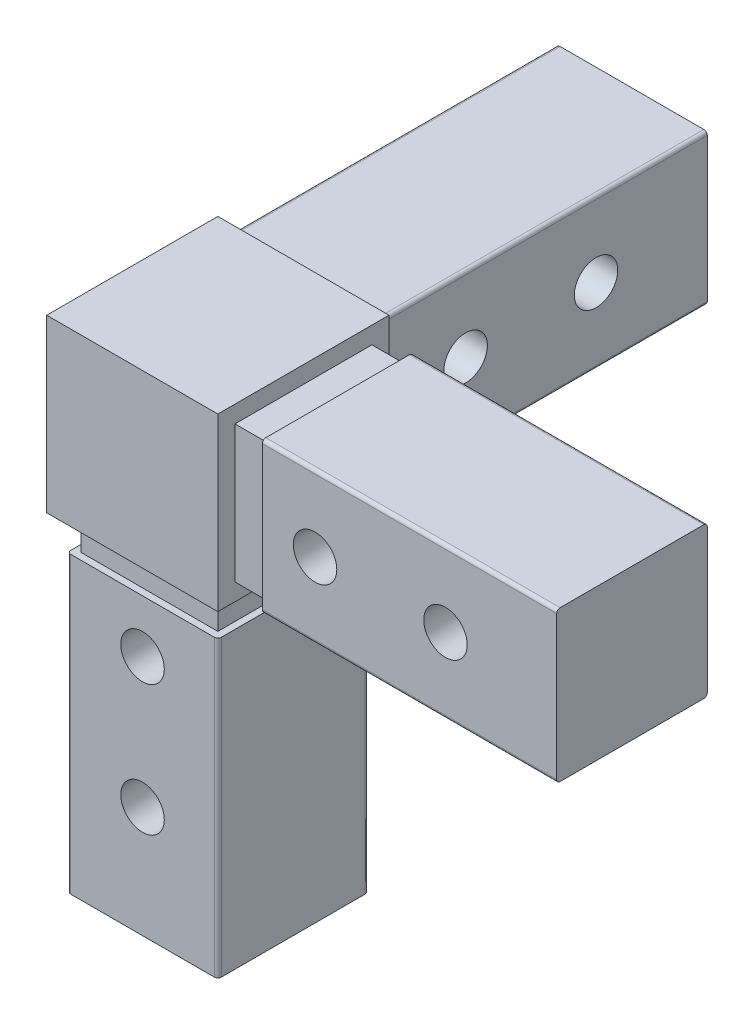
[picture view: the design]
ISO-10303-21;
HEADER;
FILE_DESCRIPTION(('STEP AP214'),'2;1');
FILE_NAME('part.step','',(''),(''),'','','');
FILE_SCHEMA(('AUTOMOTIVE_DESIGN { 1 0 10303 214 1 1 1 1 }'));
ENDSEC;
DATA;
#1=APPLICATION_CONTEXT('core data for automotive mechanical design processes');
#2=APPLICATION_PROTOCOL_DEFINITION('international standard','automotive_design',2000,#1);
#3=PRODUCT_CONTEXT('',#1,'mechanical');
#4=PRODUCT('Part','Part','',(#3));
#5=PRODUCT_RELATED_PRODUCT_CATEGORY('part','',(#4));
#6=PRODUCT_DEFINITION_FORMATION('','',#4);
#7=PRODUCT_DEFINITION_CONTEXT('part definition',#1,'design');
#8=PRODUCT_DEFINITION('design','',#6,#7);
#9=PRODUCT_DEFINITION_SHAPE('','',#8);
#10=(LENGTH_UNIT() NAMED_UNIT(*) SI_UNIT(.MILLI.,.METRE.));
#11=(NAMED_UNIT(*) PLANE_ANGLE_UNIT() SI_UNIT($,.RADIAN.));
#12=(NAMED_UNIT(*) SI_UNIT($,.STERADIAN.) SOLID_ANGLE_UNIT());
#13=UNCERTAINTY_MEASURE_WITH_UNIT(LENGTH_MEASURE(1.E-05),#10,'distance_accuracy_value','');
#14=(GEOMETRIC_REPRESENTATION_CONTEXT(3) GLOBAL_UNCERTAINTY_ASSIGNED_CONTEXT((#13)) GLOBAL_UNIT_ASSIGNED_CONTEXT((#10,
#11,#12)) REPRESENTATION_CONTEXT('',''));
#15=CARTESIAN_POINT('',(0.,0.,0.));
#16=DIRECTION('',(0.,0.,1.));
#17=DIRECTION('',(1.,0.,0.));
#18=AXIS2_PLACEMENT_3D('',#15,#16,#17);
#19=CARTESIAN_POINT('',(0.,0.,-12.5));
#20=DIRECTION('',(0.,0.,1.));
#21=DIRECTION('',(1.,0.,0.));
#22=AXIS2_PLACEMENT_3D('',#19,#20,#21);
#23=PLANE('',#22);
#24=DIRECTION('',(0.,1.,0.));
#25=VECTOR('',#24,1.);
#26=CARTESIAN_POINT('',(-12.5,12.5,-12.5));
#27=LINE('',#26,#25);
#28=CARTESIAN_POINT('',(-12.5,-12.5,-12.5));
#29=VERTEX_POINT('',#28);
#30=CARTESIAN_POINT('',(-12.5,12.5,-12.5));
#31=VERTEX_POINT('',#30);
#32=EDGE_CURVE('E502',#29,#31,#27,.T.);
#33=ORIENTED_EDGE('',*,*,#32,.T.);
#34=DIRECTION('',(1.,0.,0.));
#35=VECTOR('',#34,1.);
#36=CARTESIAN_POINT('',(12.5,12.5,-12.5));
#37=LINE('',#36,#35);
#38=CARTESIAN_POINT('',(12.5,12.5,-12.5));
#39=VERTEX_POINT('',#38);
#40=EDGE_CURVE('E505',#31,#39,#37,.T.);
#41=ORIENTED_EDGE('',*,*,#40,.T.);
#42=DIRECTION('',(0.,-1.,0.));
#43=VECTOR('',#42,1.);
#44=CARTESIAN_POINT('',(12.5,-12.5,-12.5));
#45=LINE('',#44,#43);
#46=CARTESIAN_POINT('',(12.5,-12.5,-12.5));
#47=VERTEX_POINT('',#46);
#48=EDGE_CURVE('E509',#39,#47,#45,.T.);
#49=ORIENTED_EDGE('',*,*,#48,.T.);
#50=DIRECTION('',(-1.,0.,0.));
#51=VECTOR('',#50,1.);
#52=CARTESIAN_POINT('',(-12.5,-12.5,-12.5));
#53=LINE('',#52,#51);
#54=EDGE_CURVE('E512',#47,#29,#53,.T.);
#55=ORIENTED_EDGE('',*,*,#54,.T.);
#56=EDGE_LOOP('',(#33,#41,#49,#55));
#57=FACE_BOUND('',#56,.T.);
#58=DIRECTION('',(0.,1.,0.));
#59=VECTOR('',#58,1.);
#60=CARTESIAN_POINT('',(-11.,11.,-12.5));
#61=LINE('',#60,#59);
#62=CARTESIAN_POINT('',(-11.,-10.4999999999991,-12.5));
#63=VERTEX_POINT('',#62);
#64=CARTESIAN_POINT('',(-11.,10.4999999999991,-12.5));
#65=VERTEX_POINT('',#64);
#66=EDGE_CURVE('E461',#63,#65,#61,.T.);
#67=ORIENTED_EDGE('',*,*,#66,.F.);
#68=CARTESIAN_POINT('',(-10.4999999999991,-10.4999999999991,-12.5));
#69=DIRECTION('',(0.,0.,1.));
#70=DIRECTION('',(1.,0.,0.));
#71=AXIS2_PLACEMENT_3D('',#68,#69,#70);
#72=CIRCLE('',#71,0.500000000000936);
#73=CARTESIAN_POINT('',(-10.4999999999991,-11.,-12.5));
#74=VERTEX_POINT('',#73);
#75=EDGE_CURVE('E11',#63,#74,#72,.T.);
#76=ORIENTED_EDGE('',*,*,#75,.T.);
#77=DIRECTION('',(-1.,0.,0.));
#78=VECTOR('',#77,1.);
#79=CARTESIAN_POINT('',(-11.,-11.,-12.5));
#80=LINE('',#79,#78);
#81=CARTESIAN_POINT('',(10.4999999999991,-11.,-12.5));
#82=VERTEX_POINT('',#81);
#83=EDGE_CURVE('E485',#82,#74,#80,.T.);
#84=ORIENTED_EDGE('',*,*,#83,.F.);
#85=CARTESIAN_POINT('',(10.4999999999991,-10.4999999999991,-12.5));
#86=DIRECTION('',(0.,0.,1.));
#87=DIRECTION('',(1.,0.,0.));
#88=AXIS2_PLACEMENT_3D('',#85,#86,#87);
#89=CIRCLE('',#88,0.500000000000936);
#90=CARTESIAN_POINT('',(11.,-10.4999999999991,-12.5));
#91=VERTEX_POINT('',#90);
#92=EDGE_CURVE('E445',#82,#91,#89,.T.);
#93=ORIENTED_EDGE('',*,*,#92,.T.);
#94=DIRECTION('',(0.,-1.,0.));
#95=VECTOR('',#94,1.);
#96=CARTESIAN_POINT('',(11.,-11.,-12.5));
#97=LINE('',#96,#95);
#98=CARTESIAN_POINT('',(11.,10.4999999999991,-12.5));
#99=VERTEX_POINT('',#98);
#100=EDGE_CURVE('E452',#99,#91,#97,.T.);
#101=ORIENTED_EDGE('',*,*,#100,.F.);
#102=CARTESIAN_POINT('',(10.4999999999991,10.4999999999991,-12.5));
#103=DIRECTION('',(0.,0.,1.));
#104=DIRECTION('',(1.,0.,0.));
#105=AXIS2_PLACEMENT_3D('',#102,#103,#104);
#106=CIRCLE('',#105,0.500000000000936);
#107=CARTESIAN_POINT('',(10.4999999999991,11.,-12.5));
#108=VERTEX_POINT('',#107);
#109=EDGE_CURVE('E447',#99,#108,#106,.T.);
#110=ORIENTED_EDGE('',*,*,#109,.T.);
#111=DIRECTION('',(1.,0.,0.));
#112=VECTOR('',#111,1.);
#113=CARTESIAN_POINT('',(11.,11.,-12.5));
#114=LINE('',#113,#112);
#115=CARTESIAN_POINT('',(-10.4999999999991,11.,-12.5));
#116=VERTEX_POINT('',#115);
#117=EDGE_CURVE('E450',#116,#108,#114,.T.);
#118=ORIENTED_EDGE('',*,*,#117,.F.);
#119=CARTESIAN_POINT('',(-10.4999999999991,10.4999999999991,-12.5));
#120=DIRECTION('',(0.,0.,1.));
#121=DIRECTION('',(1.,0.,0.));
#122=AXIS2_PLACEMENT_3D('',#119,#120,#121);
#123=CIRCLE('',#122,0.500000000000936);
#124=EDGE_CURVE('E54',#116,#65,#123,.T.);
#125=ORIENTED_EDGE('',*,*,#124,.T.);
#126=EDGE_LOOP('',(#67,#76,#84,#93,#101,#110,#118,#125));
#127=FACE_BOUND('',#126,.T.);
#128=ADVANCED_FACE('F46',(#57,#127),#23,.F.);
#129=CARTESIAN_POINT('',(0.,0.,10.));
#130=DIRECTION('',(0.,0.,1.));
#131=DIRECTION('',(1.,0.,0.));
#132=AXIS2_PLACEMENT_3D('',#129,#130,#131);
#133=PLANE('',#132);
#134=DIRECTION('',(-1.,0.,0.));
#135=VECTOR('',#134,1.);
#136=CARTESIAN_POINT('',(17.5,-10.,10.));
#137=LINE('',#136,#135);
#138=CARTESIAN_POINT('',(17.5,-10.,10.));
#139=VERTEX_POINT('',#138);
#140=CARTESIAN_POINT('',(12.5,-10.,10.));
#141=VERTEX_POINT('',#140);
#142=EDGE_CURVE('E283',#139,#141,#137,.T.);
#143=ORIENTED_EDGE('',*,*,#142,.F.);
#144=DIRECTION('',(0.,-1.,0.));
#145=VECTOR('',#144,1.);
#146=CARTESIAN_POINT('',(17.5,-11.,10.));
#147=LINE('',#146,#145);
#148=CARTESIAN_POINT('',(17.5,10.,10.));
#149=VERTEX_POINT('',#148);
#150=EDGE_CURVE('E278',#149,#139,#147,.T.);
#151=ORIENTED_EDGE('',*,*,#150,.F.);
#152=DIRECTION('',(-1.,0.,0.));
#153=VECTOR('',#152,1.);
#154=CARTESIAN_POINT('',(12.5,10.,10.));
#155=LINE('',#154,#153);
#156=CARTESIAN_POINT('',(12.5,10.,10.));
#157=VERTEX_POINT('',#156);
#158=EDGE_CURVE('E282',#149,#157,#155,.T.);
#159=ORIENTED_EDGE('',*,*,#158,.T.);
#160=DIRECTION('',(0.,1.,0.));
#161=VECTOR('',#160,1.);
#162=CARTESIAN_POINT('',(12.5,12.5,10.));
#163=LINE('',#162,#161);
#164=EDGE_CURVE('E532',#141,#157,#163,.T.);
#165=ORIENTED_EDGE('',*,*,#164,.F.);
#166=EDGE_LOOP('',(#143,#151,#159,#165));
#167=FACE_BOUND('',#166,.T.);
#168=ADVANCED_FACE('F280',(#167),#133,.T.);
#169=CARTESIAN_POINT('',(17.5,-10.,-10.));
#170=DIRECTION('',(0.,1.,0.));
#171=DIRECTION('',(0.,0.,1.));
#172=AXIS2_PLACEMENT_3D('',#169,#170,#171);
#173=PLANE('',#172);
#174=DIRECTION('',(0.,0.,-1.));
#175=VECTOR('',#174,1.);
#176=CARTESIAN_POINT('',(17.5,-10.,-11.));
#177=LINE('',#176,#175);
#178=CARTESIAN_POINT('',(17.5,-10.,-10.));
#179=VERTEX_POINT('',#178);
#180=EDGE_CURVE('E492',#139,#179,#177,.T.);
#181=ORIENTED_EDGE('',*,*,#180,.F.);
#182=ORIENTED_EDGE('',*,*,#142,.T.);
#183=DIRECTION('',(0.,0.,-1.));
#184=VECTOR('',#183,1.);
#185=CARTESIAN_POINT('',(12.5,-10.,-10.));
#186=LINE('',#185,#184);
#187=CARTESIAN_POINT('',(12.5,-10.,-10.));
#188=VERTEX_POINT('',#187);
#189=EDGE_CURVE('E311',#141,#188,#186,.T.);
#190=ORIENTED_EDGE('',*,*,#189,.T.);
#191=DIRECTION('',(-1.,0.,0.));
#192=VECTOR('',#191,1.);
#193=CARTESIAN_POINT('',(17.5,-10.,-10.));
#194=LINE('',#193,#192);
#195=EDGE_CURVE('E307',#179,#188,#194,.T.);
#196=ORIENTED_EDGE('',*,*,#195,.F.);
#197=EDGE_LOOP('',(#181,#182,#190,#196));
#198=FACE_BOUND('',#197,.T.);
#199=ADVANCED_FACE('F631',(#198),#173,.F.);
#200=CARTESIAN_POINT('',(0.,0.,-10.));
#201=DIRECTION('',(0.,0.,1.));
#202=DIRECTION('',(1.,0.,0.));
#203=AXIS2_PLACEMENT_3D('',#200,#201,#202);
#204=PLANE('',#203);
#205=DIRECTION('',(0.,-1.,0.));
#206=VECTOR('',#205,1.);
#207=CARTESIAN_POINT('',(12.5,-12.5,-10.));
#208=LINE('',#207,#206);
#209=CARTESIAN_POINT('',(12.5,10.,-10.));
#210=VERTEX_POINT('',#209);
#211=EDGE_CURVE('E500',#210,#188,#208,.T.);
#212=ORIENTED_EDGE('',*,*,#211,.F.);
#213=DIRECTION('',(-1.,0.,0.));
#214=VECTOR('',#213,1.);
#215=CARTESIAN_POINT('',(12.5,10.,-10.));
#216=LINE('',#215,#214);
#217=CARTESIAN_POINT('',(17.5,10.,-10.));
#218=VERTEX_POINT('',#217);
#219=EDGE_CURVE('E339',#218,#210,#216,.T.);
#220=ORIENTED_EDGE('',*,*,#219,.F.);
#221=DIRECTION('',(0.,1.,0.));
#222=VECTOR('',#221,1.);
#223=CARTESIAN_POINT('',(17.5,10.,-10.));
#224=LINE('',#223,#222);
#225=EDGE_CURVE('E306',#179,#218,#224,.T.);
#226=ORIENTED_EDGE('',*,*,#225,.F.);
#227=ORIENTED_EDGE('',*,*,#195,.T.);
#228=EDGE_LOOP('',(#212,#220,#226,#227));
#229=FACE_BOUND('',#228,.T.);
#230=ADVANCED_FACE('F746',(#229),#204,.F.);
#231=DIRECTION('',(-1.,0.,0.));
#232=VECTOR('',#231,1.);
#233=CARTESIAN_POINT('',(-12.5,-12.5,-10.));
#234=LINE('',#233,#232);
#235=CARTESIAN_POINT('',(10.,-12.5,-10.));
#236=VERTEX_POINT('',#235);
#237=CARTESIAN_POINT('',(-10.,-12.5,-10.));
#238=VERTEX_POINT('',#237);
#239=EDGE_CURVE('E506',#236,#238,#234,.T.);
#240=ORIENTED_EDGE('',*,*,#239,.F.);
#241=DIRECTION('',(0.,1.,0.));
#242=VECTOR('',#241,1.);
#243=CARTESIAN_POINT('',(10.,-17.5,-10.));
#244=LINE('',#243,#242);
#245=CARTESIAN_POINT('',(10.,-17.5,-10.));
#246=VERTEX_POINT('',#245);
#247=EDGE_CURVE('E301',#246,#236,#244,.T.);
#248=ORIENTED_EDGE('',*,*,#247,.F.);
#249=DIRECTION('',(1.,0.,0.));
#250=VECTOR('',#249,1.);
#251=CARTESIAN_POINT('',(10.,-17.5,-10.));
#252=LINE('',#251,#250);
#253=CARTESIAN_POINT('',(-10.,-17.5,-10.));
#254=VERTEX_POINT('',#253);
#255=EDGE_CURVE('E320',#254,#246,#252,.T.);
#256=ORIENTED_EDGE('',*,*,#255,.F.);
#257=DIRECTION('',(0.,-1.,0.));
#258=VECTOR('',#257,1.);
#259=CARTESIAN_POINT('',(-10.,10.,-10.));
#260=LINE('',#259,#258);
#261=EDGE_CURVE('E341',#238,#254,#260,.T.);
#262=ORIENTED_EDGE('',*,*,#261,.F.);
#263=EDGE_LOOP('',(#240,#248,#256,#262));
#264=FACE_BOUND('',#263,.T.);
#265=ADVANCED_FACE('F734',(#264),#204,.F.);
#266=CARTESIAN_POINT('',(-10.,10.,-10.));
#267=DIRECTION('',(-1.,0.,0.));
#268=DIRECTION('',(0.,0.,1.));
#269=AXIS2_PLACEMENT_3D('',#266,#267,#268);
#270=PLANE('',#269);
#271=DIRECTION('',(0.,-1.,0.));
#272=VECTOR('',#271,1.);
#273=CARTESIAN_POINT('',(-10.,10.,10.));
#274=LINE('',#273,#272);
#275=CARTESIAN_POINT('',(-10.,-12.5,10.));
#276=VERTEX_POINT('',#275);
#277=CARTESIAN_POINT('',(-10.,-17.5,10.));
#278=VERTEX_POINT('',#277);
#279=EDGE_CURVE('E300',#276,#278,#274,.T.);
#280=ORIENTED_EDGE('',*,*,#279,.F.);
#281=DIRECTION('',(0.,0.,1.));
#282=VECTOR('',#281,1.);
#283=CARTESIAN_POINT('',(-10.,-12.5,12.5));
#284=LINE('',#283,#282);
#285=EDGE_CURVE('E515',#238,#276,#284,.T.);
#286=ORIENTED_EDGE('',*,*,#285,.F.);
#287=ORIENTED_EDGE('',*,*,#261,.T.);
#288=DIRECTION('',(0.,0.,-1.));
#289=VECTOR('',#288,1.);
#290=CARTESIAN_POINT('',(-10.,-17.5,-10.));
#291=LINE('',#290,#289);
#292=EDGE_CURVE('E329',#278,#254,#291,.T.);
#293=ORIENTED_EDGE('',*,*,#292,.F.);
#294=EDGE_LOOP('',(#280,#286,#287,#293));
#295=FACE_BOUND('',#294,.T.);
#296=ADVANCED_FACE('F731',(#295),#270,.T.);
#297=DIRECTION('',(0.,1.,0.));
#298=VECTOR('',#297,1.);
#299=CARTESIAN_POINT('',(10.,-17.5,10.));
#300=LINE('',#299,#298);
#301=CARTESIAN_POINT('',(10.,-17.5,10.));
#302=VERTEX_POINT('',#301);
#303=CARTESIAN_POINT('',(10.,-12.5,10.));
#304=VERTEX_POINT('',#303);
#305=EDGE_CURVE('E332',#302,#304,#300,.T.);
#306=ORIENTED_EDGE('',*,*,#305,.T.);
#307=DIRECTION('',(1.,0.,0.));
#308=VECTOR('',#307,1.);
#309=CARTESIAN_POINT('',(12.5,-12.5,10.));
#310=LINE('',#309,#308);
#311=EDGE_CURVE('E526',#276,#304,#310,.T.);
#312=ORIENTED_EDGE('',*,*,#311,.F.);
#313=ORIENTED_EDGE('',*,*,#279,.T.);
#314=DIRECTION('',(-1.,0.,0.));
#315=VECTOR('',#314,1.);
#316=CARTESIAN_POINT('',(-10.,-17.5,10.));
#317=LINE('',#316,#315);
#318=EDGE_CURVE('E326',#302,#278,#317,.T.);
#319=ORIENTED_EDGE('',*,*,#318,.F.);
#320=EDGE_LOOP('',(#306,#312,#313,#319));
#321=FACE_BOUND('',#320,.T.);
#322=ADVANCED_FACE('F633',(#321),#133,.T.);
#323=CARTESIAN_POINT('',(12.5,10.,-10.));
#324=DIRECTION('',(0.,1.,0.));
#325=DIRECTION('',(-1.,0.,0.));
#326=AXIS2_PLACEMENT_3D('',#323,#324,#325);
#327=PLANE('',#326);
#328=ORIENTED_EDGE('',*,*,#219,.T.);
#329=DIRECTION('',(0.,0.,-1.));
#330=VECTOR('',#329,1.);
#331=CARTESIAN_POINT('',(12.5,10.,-10.));
#332=LINE('',#331,#330);
#333=EDGE_CURVE('E299',#157,#210,#332,.T.);
#334=ORIENTED_EDGE('',*,*,#333,.F.);
#335=ORIENTED_EDGE('',*,*,#158,.F.);
#336=DIRECTION('',(0.,0.,1.));
#337=VECTOR('',#336,1.);
#338=CARTESIAN_POINT('',(17.5,10.,10.));
#339=LINE('',#338,#337);
#340=EDGE_CURVE('E296',#218,#149,#339,.T.);
#341=ORIENTED_EDGE('',*,*,#340,.F.);
#342=EDGE_LOOP('',(#328,#334,#335,#341));
#343=FACE_BOUND('',#342,.T.);
#344=ADVANCED_FACE('F295',(#343),#327,.T.);
#345=CARTESIAN_POINT('',(12.5,-12.5,-10.));
#346=DIRECTION('',(1.,0.,0.));
#347=DIRECTION('',(0.,0.,-1.));
#348=AXIS2_PLACEMENT_3D('',#345,#346,#347);
#349=PLANE('',#348);
#350=ORIENTED_EDGE('',*,*,#333,.T.);
#351=ORIENTED_EDGE('',*,*,#211,.T.);
#352=ORIENTED_EDGE('',*,*,#189,.F.);
#353=ORIENTED_EDGE('',*,*,#164,.T.);
#354=EDGE_LOOP('',(#350,#351,#352,#353));
#355=FACE_BOUND('',#354,.T.);
#356=ORIENTED_EDGE('',*,*,#48,.F.);
#357=DIRECTION('',(0.,0.,-1.));
#358=VECTOR('',#357,1.);
#359=CARTESIAN_POINT('',(12.5,12.5,-10.));
#360=LINE('',#359,#358);
#361=CARTESIAN_POINT('',(12.5,12.5,12.5));
#362=VERTEX_POINT('',#361);
#363=EDGE_CURVE('E539',#362,#39,#360,.T.);
#364=ORIENTED_EDGE('',*,*,#363,.F.);
#365=DIRECTION('',(0.,1.,0.));
#366=VECTOR('',#365,1.);
#367=CARTESIAN_POINT('',(12.5,12.5,12.5));
#368=LINE('',#367,#366);
#369=CARTESIAN_POINT('',(12.5,-12.5,12.5));
#370=VERTEX_POINT('',#369);
#371=EDGE_CURVE('E531',#370,#362,#368,.T.);
#372=ORIENTED_EDGE('',*,*,#371,.F.);
#373=DIRECTION('',(0.,0.,1.));
#374=VECTOR('',#373,1.);
#375=CARTESIAN_POINT('',(12.5,-12.5,-10.));
#376=LINE('',#375,#374);
#377=EDGE_CURVE('E342',#47,#370,#376,.T.);
#378=ORIENTED_EDGE('',*,*,#377,.F.);
#379=EDGE_LOOP('',(#356,#364,#372,#378));
#380=FACE_BOUND('',#379,.T.);
#381=ADVANCED_FACE('F730',(#355,#380),#349,.T.);
#382=CARTESIAN_POINT('',(-10.,-12.5,-10.));
#383=DIRECTION('',(0.,-1.,0.));
#384=DIRECTION('',(0.,0.,-1.));
#385=AXIS2_PLACEMENT_3D('',#382,#383,#384);
#386=PLANE('',#385);
#387=ORIENTED_EDGE('',*,*,#54,.F.);
#388=ORIENTED_EDGE('',*,*,#377,.T.);
#389=DIRECTION('',(1.,0.,0.));
#390=VECTOR('',#389,1.);
#391=CARTESIAN_POINT('',(12.5,-12.5,12.5));
#392=LINE('',#391,#390);
#393=CARTESIAN_POINT('',(-12.5,-12.5,12.5));
#394=VERTEX_POINT('',#393);
#395=EDGE_CURVE('E528',#394,#370,#392,.T.);
#396=ORIENTED_EDGE('',*,*,#395,.F.);
#397=DIRECTION('',(0.,0.,1.));
#398=VECTOR('',#397,1.);
#399=CARTESIAN_POINT('',(-12.5,-12.5,12.5));
#400=LINE('',#399,#398);
#401=EDGE_CURVE('E518',#29,#394,#400,.T.);
#402=ORIENTED_EDGE('',*,*,#401,.F.);
#403=EDGE_LOOP('',(#387,#388,#396,#402));
#404=FACE_BOUND('',#403,.T.);
#405=DIRECTION('',(0.,0.,1.));
#406=VECTOR('',#405,1.);
#407=CARTESIAN_POINT('',(10.,-12.5,10.));
#408=LINE('',#407,#406);
#409=EDGE_CURVE('E319',#236,#304,#408,.T.);
#410=ORIENTED_EDGE('',*,*,#409,.F.);
#411=ORIENTED_EDGE('',*,*,#239,.T.);
#412=ORIENTED_EDGE('',*,*,#285,.T.);
#413=ORIENTED_EDGE('',*,*,#311,.T.);
#414=EDGE_LOOP('',(#410,#411,#412,#413));
#415=FACE_BOUND('',#414,.T.);
#416=ADVANCED_FACE('F736',(#404,#415),#386,.T.);
#417=CARTESIAN_POINT('',(10.,-17.5,10.));
#418=DIRECTION('',(-1.,0.,0.));
#419=DIRECTION('',(0.,0.,1.));
#420=AXIS2_PLACEMENT_3D('',#417,#418,#419);
#421=PLANE('',#420);
#422=ORIENTED_EDGE('',*,*,#409,.T.);
#423=ORIENTED_EDGE('',*,*,#305,.F.);
#424=DIRECTION('',(0.,0.,1.));
#425=VECTOR('',#424,1.);
#426=CARTESIAN_POINT('',(10.,-17.5,10.));
#427=LINE('',#426,#425);
#428=EDGE_CURVE('E323',#246,#302,#427,.T.);
#429=ORIENTED_EDGE('',*,*,#428,.F.);
#430=ORIENTED_EDGE('',*,*,#247,.T.);
#431=EDGE_LOOP('',(#422,#423,#429,#430));
#432=FACE_BOUND('',#431,.T.);
#433=ADVANCED_FACE('F739',(#432),#421,.F.);
#434=CARTESIAN_POINT('',(60.5,11.,-11.));
#435=DIRECTION('',(0.,0.,1.));
#436=DIRECTION('',(0.,-1.,0.));
#437=AXIS2_PLACEMENT_3D('',#434,#435,#436);
#438=PLANE('',#437);
#439=CARTESIAN_POINT('',(44.25,0.,-11.));
#440=DIRECTION('',(0.,0.,1.));
#441=DIRECTION('',(0.,-1.,0.));
#442=AXIS2_PLACEMENT_3D('',#439,#440,#441);
#443=CIRCLE('',#442,3.175);
#444=CARTESIAN_POINT('',(44.25,-3.175,-11.));
#445=VERTEX_POINT('',#444);
#446=EDGE_CURVE('E482',#445,#445,#443,.F.);
#447=ORIENTED_EDGE('',*,*,#446,.F.);
#448=EDGE_LOOP('',(#447));
#449=FACE_BOUND('',#448,.T.);
#450=CARTESIAN_POINT('',(25.2,0.,-11.));
#451=DIRECTION('',(0.,0.,1.));
#452=DIRECTION('',(0.,-1.,0.));
#453=AXIS2_PLACEMENT_3D('',#450,#451,#452);
#454=CIRCLE('',#453,3.175);
#455=CARTESIAN_POINT('',(25.2,-3.175,-11.));
#456=VERTEX_POINT('',#455);
#457=EDGE_CURVE('E1460',#456,#456,#454,.F.);
#458=ORIENTED_EDGE('',*,*,#457,.F.);
#459=EDGE_LOOP('',(#458));
#460=FACE_BOUND('',#459,.T.);
#461=DIRECTION('',(0.,1.,0.));
#462=VECTOR('',#461,1.);
#463=CARTESIAN_POINT('',(17.5,11.,-11.));
#464=LINE('',#463,#462);
#465=CARTESIAN_POINT('',(17.5,-10.4999999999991,-11.));
#466=VERTEX_POINT('',#465);
#467=CARTESIAN_POINT('',(17.5,10.4999999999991,-11.));
#468=VERTEX_POINT('',#467);
#469=EDGE_CURVE('E556',#466,#468,#464,.T.);
#470=ORIENTED_EDGE('',*,*,#469,.T.);
#471=DIRECTION('',(-1.,0.,0.));
#472=VECTOR('',#471,1.);
#473=CARTESIAN_POINT('',(60.5,10.4999999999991,-11.));
#474=LINE('',#473,#472);
#475=CARTESIAN_POINT('',(60.5,10.4999999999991,-11.));
#476=VERTEX_POINT('',#475);
#477=EDGE_CURVE('E406',#468,#476,#474,.F.);
#478=ORIENTED_EDGE('',*,*,#477,.T.);
#479=DIRECTION('',(0.,1.,0.));
#480=VECTOR('',#479,1.);
#481=CARTESIAN_POINT('',(60.5,11.,-11.));
#482=LINE('',#481,#480);
#483=CARTESIAN_POINT('',(60.5,-10.4999999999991,-11.));
#484=VERTEX_POINT('',#483);
#485=EDGE_CURVE('E567',#484,#476,#482,.T.);
#486=ORIENTED_EDGE('',*,*,#485,.F.);
#487=DIRECTION('',(1.,0.,0.));
#488=VECTOR('',#487,1.);
#489=CARTESIAN_POINT('',(60.5,-10.4999999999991,-11.));
#490=LINE('',#489,#488);
#491=EDGE_CURVE('E404',#484,#466,#490,.F.);
#492=ORIENTED_EDGE('',*,*,#491,.T.);
#493=EDGE_LOOP('',(#470,#478,#486,#492));
#494=FACE_BOUND('',#493,.T.);
#495=ADVANCED_FACE('F608',(#449,#460,#494),#438,.F.);
#496=CARTESIAN_POINT('',(60.5,11.,10.));
#497=DIRECTION('',(0.,-1.,0.));
#498=DIRECTION('',(0.,0.,-1.));
#499=AXIS2_PLACEMENT_3D('',#496,#497,#498);
#500=PLANE('',#499);
#501=DIRECTION('',(0.,0.,1.));
#502=VECTOR('',#501,1.);
#503=CARTESIAN_POINT('',(60.5,11.,10.));
#504=LINE('',#503,#502);
#505=CARTESIAN_POINT('',(60.5,11.,-10.4999999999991));
#506=VERTEX_POINT('',#505);
#507=CARTESIAN_POINT('',(60.5,11.,10.4999999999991));
#508=VERTEX_POINT('',#507);
#509=EDGE_CURVE('E316',#506,#508,#504,.T.);
#510=ORIENTED_EDGE('',*,*,#509,.F.);
#511=DIRECTION('',(-1.,0.,0.));
#512=VECTOR('',#511,1.);
#513=CARTESIAN_POINT('',(60.5,11.,-10.4999999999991));
#514=LINE('',#513,#512);
#515=CARTESIAN_POINT('',(17.5,11.,-10.4999999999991));
#516=VERTEX_POINT('',#515);
#517=EDGE_CURVE('E401',#506,#516,#514,.T.);
#518=ORIENTED_EDGE('',*,*,#517,.T.);
#519=DIRECTION('',(0.,0.,1.));
#520=VECTOR('',#519,1.);
#521=CARTESIAN_POINT('',(17.5,11.,10.));
#522=LINE('',#521,#520);
#523=CARTESIAN_POINT('',(17.5,11.,10.4999999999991));
#524=VERTEX_POINT('',#523);
#525=EDGE_CURVE('E570',#516,#524,#522,.T.);
#526=ORIENTED_EDGE('',*,*,#525,.T.);
#527=DIRECTION('',(-1.,0.,0.));
#528=VECTOR('',#527,1.);
#529=CARTESIAN_POINT('',(60.5,11.,10.4999999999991));
#530=LINE('',#529,#528);
#531=EDGE_CURVE('E399',#524,#508,#530,.F.);
#532=ORIENTED_EDGE('',*,*,#531,.T.);
#533=EDGE_LOOP('',(#510,#518,#526,#532));
#534=FACE_BOUND('',#533,.T.);
#535=ADVANCED_FACE('F579',(#534),#500,.F.);
#536=CARTESIAN_POINT('',(60.5,0.,0.));
#537=DIRECTION('',(-1.,0.,0.));
#538=DIRECTION('',(0.,0.,1.));
#539=AXIS2_PLACEMENT_3D('',#536,#537,#538);
#540=PLANE('',#539);
#541=DIRECTION('',(0.,1.,0.));
#542=VECTOR('',#541,1.);
#543=CARTESIAN_POINT('',(60.5,11.,11.));
#544=LINE('',#543,#542);
#545=CARTESIAN_POINT('',(60.5,-10.4999999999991,11.));
#546=VERTEX_POINT('',#545);
#547=CARTESIAN_POINT('',(60.5,10.4999999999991,11.));
#548=VERTEX_POINT('',#547);
#549=EDGE_CURVE('E490',#546,#548,#544,.T.);
#550=ORIENTED_EDGE('',*,*,#549,.F.);
#551=CARTESIAN_POINT('',(60.5,-10.4999999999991,10.4999999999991));
#552=DIRECTION('',(-1.,0.,0.));
#553=DIRECTION('',(0.,0.,1.));
#554=AXIS2_PLACEMENT_3D('',#551,#552,#553);
#555=CIRCLE('',#554,0.500000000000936);
#556=CARTESIAN_POINT('',(60.5,-11.,10.4999999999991));
#557=VERTEX_POINT('',#556);
#558=EDGE_CURVE('E384',#546,#557,#555,.F.);
#559=ORIENTED_EDGE('',*,*,#558,.T.);
#560=DIRECTION('',(0.,0.,1.));
#561=VECTOR('',#560,1.);
#562=CARTESIAN_POINT('',(60.5,-11.,10.));
#563=LINE('',#562,#561);
#564=CARTESIAN_POINT('',(60.5,-11.,-10.4999999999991));
#565=VERTEX_POINT('',#564);
#566=EDGE_CURVE('E497',#565,#557,#563,.T.);
#567=ORIENTED_EDGE('',*,*,#566,.F.);
#568=CARTESIAN_POINT('',(60.5,-10.4999999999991,-10.4999999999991));
#569=DIRECTION('',(-1.,0.,0.));
#570=DIRECTION('',(0.,0.,1.));
#571=AXIS2_PLACEMENT_3D('',#568,#569,#570);
#572=CIRCLE('',#571,0.500000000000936);
#573=EDGE_CURVE('E378',#565,#484,#572,.F.);
#574=ORIENTED_EDGE('',*,*,#573,.T.);
#575=ORIENTED_EDGE('',*,*,#485,.T.);
#576=CARTESIAN_POINT('',(60.5,10.4999999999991,-10.4999999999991));
#577=DIRECTION('',(-1.,0.,0.));
#578=DIRECTION('',(0.,0.,1.));
#579=AXIS2_PLACEMENT_3D('',#576,#577,#578);
#580=CIRCLE('',#579,0.500000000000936);
#581=EDGE_CURVE('E382',#476,#506,#580,.F.);
#582=ORIENTED_EDGE('',*,*,#581,.T.);
#583=ORIENTED_EDGE('',*,*,#509,.T.);
#584=CARTESIAN_POINT('',(60.5,10.4999999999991,10.4999999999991));
#585=DIRECTION('',(-1.,0.,0.));
#586=DIRECTION('',(0.,0.,1.));
#587=AXIS2_PLACEMENT_3D('',#584,#585,#586);
#588=CIRCLE('',#587,0.500000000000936);
#589=EDGE_CURVE('E380',#508,#548,#588,.F.);
#590=ORIENTED_EDGE('',*,*,#589,.T.);
#591=EDGE_LOOP('',(#550,#559,#567,#574,#575,#582,#583,#590));
#592=FACE_BOUND('',#591,.T.);
#593=ADVANCED_FACE('F587',(#592),#540,.F.);
#594=CARTESIAN_POINT('',(17.5,0.,0.));
#595=DIRECTION('',(-1.,0.,0.));
#596=DIRECTION('',(0.,0.,1.));
#597=AXIS2_PLACEMENT_3D('',#594,#595,#596);
#598=PLANE('',#597);
#599=ORIENTED_EDGE('',*,*,#340,.T.);
#600=ORIENTED_EDGE('',*,*,#150,.T.);
#601=ORIENTED_EDGE('',*,*,#180,.T.);
#602=ORIENTED_EDGE('',*,*,#225,.T.);
#603=EDGE_LOOP('',(#599,#600,#601,#602));
#604=FACE_BOUND('',#603,.T.);
#605=DIRECTION('',(0.,0.,-1.));
#606=VECTOR('',#605,1.);
#607=CARTESIAN_POINT('',(17.5,-11.,-11.));
#608=LINE('',#607,#606);
#609=CARTESIAN_POINT('',(17.5,-11.,10.4999999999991));
#610=VERTEX_POINT('',#609);
#611=CARTESIAN_POINT('',(17.5,-11.,-10.4999999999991));
#612=VERTEX_POINT('',#611);
#613=EDGE_CURVE('E494',#610,#612,#608,.T.);
#614=ORIENTED_EDGE('',*,*,#613,.F.);
#615=CARTESIAN_POINT('',(17.5,-10.4999999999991,10.4999999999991));
#616=DIRECTION('',(-1.,0.,0.));
#617=DIRECTION('',(0.,0.,1.));
#618=AXIS2_PLACEMENT_3D('',#615,#616,#617);
#619=CIRCLE('',#618,0.500000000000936);
#620=CARTESIAN_POINT('',(17.5,-10.4999999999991,11.));
#621=VERTEX_POINT('',#620);
#622=EDGE_CURVE('E397',#610,#621,#619,.T.);
#623=ORIENTED_EDGE('',*,*,#622,.T.);
#624=DIRECTION('',(0.,-1.,0.));
#625=VECTOR('',#624,1.);
#626=CARTESIAN_POINT('',(17.5,-11.,11.));
#627=LINE('',#626,#625);
#628=CARTESIAN_POINT('',(17.5,10.4999999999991,11.));
#629=VERTEX_POINT('',#628);
#630=EDGE_CURVE('E288',#629,#621,#627,.T.);
#631=ORIENTED_EDGE('',*,*,#630,.F.);
#632=CARTESIAN_POINT('',(17.5,10.4999999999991,10.4999999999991));
#633=DIRECTION('',(-1.,0.,0.));
#634=DIRECTION('',(0.,0.,1.));
#635=AXIS2_PLACEMENT_3D('',#632,#633,#634);
#636=CIRCLE('',#635,0.500000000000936);
#637=EDGE_CURVE('E393',#629,#524,#636,.T.);
#638=ORIENTED_EDGE('',*,*,#637,.T.);
#639=ORIENTED_EDGE('',*,*,#525,.F.);
#640=CARTESIAN_POINT('',(17.5,10.4999999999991,-10.4999999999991));
#641=DIRECTION('',(-1.,0.,0.));
#642=DIRECTION('',(0.,0.,1.));
#643=AXIS2_PLACEMENT_3D('',#640,#641,#642);
#644=CIRCLE('',#643,0.500000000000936);
#645=EDGE_CURVE('E395',#516,#468,#644,.T.);
#646=ORIENTED_EDGE('',*,*,#645,.T.);
#647=ORIENTED_EDGE('',*,*,#469,.F.);
#648=CARTESIAN_POINT('',(17.5,-10.4999999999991,-10.4999999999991));
#649=DIRECTION('',(-1.,0.,0.));
#650=DIRECTION('',(0.,0.,1.));
#651=AXIS2_PLACEMENT_3D('',#648,#649,#650);
#652=CIRCLE('',#651,0.500000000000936);
#653=EDGE_CURVE('E391',#466,#612,#652,.T.);
#654=ORIENTED_EDGE('',*,*,#653,.T.);
#655=EDGE_LOOP('',(#614,#623,#631,#638,#639,#646,#647,#654));
#656=FACE_BOUND('',#655,.T.);
#657=ADVANCED_FACE('F303',(#604,#656),#598,.T.);
#658=CARTESIAN_POINT('',(11.,-60.5,-11.));
#659=DIRECTION('',(0.,0.,-1.));
#660=DIRECTION('',(-1.,0.,0.));
#661=AXIS2_PLACEMENT_3D('',#658,#659,#660);
#662=PLANE('',#661);
#663=CARTESIAN_POINT('',(0.,-44.25,-11.));
#664=DIRECTION('',(0.,0.,-1.));
#665=DIRECTION('',(-1.,0.,0.));
#666=AXIS2_PLACEMENT_3D('',#663,#664,#665);
#667=CIRCLE('',#666,3.175);
#668=CARTESIAN_POINT('',(-3.175,-44.25,-11.));
#669=VERTEX_POINT('',#668);
#670=EDGE_CURVE('E1456',#669,#669,#667,.F.);
#671=ORIENTED_EDGE('',*,*,#670,.T.);
#672=EDGE_LOOP('',(#671));
#673=FACE_BOUND('',#672,.T.);
#674=CARTESIAN_POINT('',(0.,-25.2,-11.));
#675=DIRECTION('',(0.,0.,-1.));
#676=DIRECTION('',(-1.,0.,0.));
#677=AXIS2_PLACEMENT_3D('',#674,#675,#676);
#678=CIRCLE('',#677,3.175);
#679=CARTESIAN_POINT('',(-3.175,-25.2,-11.));
#680=VERTEX_POINT('',#679);
#681=EDGE_CURVE('E1445',#680,#680,#678,.F.);
#682=ORIENTED_EDGE('',*,*,#681,.T.);
#683=EDGE_LOOP('',(#682));
#684=FACE_BOUND('',#683,.T.);
#685=DIRECTION('',(-1.,0.,0.));
#686=VECTOR('',#685,1.);
#687=CARTESIAN_POINT('',(11.,-60.5,-11.));
#688=LINE('',#687,#686);
#689=CARTESIAN_POINT('',(10.4999999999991,-60.5,-11.));
#690=VERTEX_POINT('',#689);
#691=CARTESIAN_POINT('',(-10.4999999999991,-60.5,-11.));
#692=VERTEX_POINT('',#691);
#693=EDGE_CURVE('E543',#690,#692,#688,.T.);
#694=ORIENTED_EDGE('',*,*,#693,.T.);
#695=DIRECTION('',(0.,1.,0.));
#696=VECTOR('',#695,1.);
#697=CARTESIAN_POINT('',(-10.4999999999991,-60.5,-11.));
#698=LINE('',#697,#696);
#699=CARTESIAN_POINT('',(-10.4999999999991,-17.5,-11.));
#700=VERTEX_POINT('',#699);
#701=EDGE_CURVE('E442',#692,#700,#698,.T.);
#702=ORIENTED_EDGE('',*,*,#701,.T.);
#703=DIRECTION('',(-1.,0.,0.));
#704=VECTOR('',#703,1.);
#705=CARTESIAN_POINT('',(11.,-17.5,-11.));
#706=LINE('',#705,#704);
#707=CARTESIAN_POINT('',(10.4999999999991,-17.5,-11.));
#708=VERTEX_POINT('',#707);
#709=EDGE_CURVE('E541',#708,#700,#706,.T.);
#710=ORIENTED_EDGE('',*,*,#709,.F.);
#711=DIRECTION('',(0.,1.,0.));
#712=VECTOR('',#711,1.);
#713=CARTESIAN_POINT('',(10.4999999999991,-60.5,-11.));
#714=LINE('',#713,#712);
#715=EDGE_CURVE('E440',#708,#690,#714,.F.);
#716=ORIENTED_EDGE('',*,*,#715,.T.);
#717=EDGE_LOOP('',(#694,#702,#710,#716));
#718=FACE_BOUND('',#717,.T.);
#719=ADVANCED_FACE('F614',(#673,#684,#718),#662,.T.);
#720=CARTESIAN_POINT('',(11.,-60.5,11.));
#721=DIRECTION('',(1.,0.,0.));
#722=DIRECTION('',(0.,0.,-1.));
#723=AXIS2_PLACEMENT_3D('',#720,#721,#722);
#724=PLANE('',#723);
#725=DIRECTION('',(0.,0.,-1.));
#726=VECTOR('',#725,1.);
#727=CARTESIAN_POINT('',(11.,-17.5,11.));
#728=LINE('',#727,#726);
#729=CARTESIAN_POINT('',(11.,-17.5,10.4999999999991));
#730=VERTEX_POINT('',#729);
#731=CARTESIAN_POINT('',(11.,-17.5,-10.4999999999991));
#732=VERTEX_POINT('',#731);
#733=EDGE_CURVE('E547',#730,#732,#728,.T.);
#734=ORIENTED_EDGE('',*,*,#733,.F.);
#735=DIRECTION('',(0.,1.,0.));
#736=VECTOR('',#735,1.);
#737=CARTESIAN_POINT('',(11.,-60.5,10.4999999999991));
#738=LINE('',#737,#736);
#739=CARTESIAN_POINT('',(11.,-60.5,10.4999999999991));
#740=VERTEX_POINT('',#739);
#741=EDGE_CURVE('E429',#730,#740,#738,.F.);
#742=ORIENTED_EDGE('',*,*,#741,.T.);
#743=DIRECTION('',(0.,0.,-1.));
#744=VECTOR('',#743,1.);
#745=CARTESIAN_POINT('',(11.,-60.5,11.));
#746=LINE('',#745,#744);
#747=CARTESIAN_POINT('',(11.,-60.5,-10.4999999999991));
#748=VERTEX_POINT('',#747);
#749=EDGE_CURVE('E553',#740,#748,#746,.T.);
#750=ORIENTED_EDGE('',*,*,#749,.T.);
#751=DIRECTION('',(0.,1.,0.));
#752=VECTOR('',#751,1.);
#753=CARTESIAN_POINT('',(11.,-60.5,-10.4999999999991));
#754=LINE('',#753,#752);
#755=EDGE_CURVE('E426',#748,#732,#754,.T.);
#756=ORIENTED_EDGE('',*,*,#755,.T.);
#757=EDGE_LOOP('',(#734,#742,#750,#756));
#758=FACE_BOUND('',#757,.T.);
#759=ADVANCED_FACE('F620',(#758),#724,.T.);
#760=CARTESIAN_POINT('',(-11.,-60.5,11.));
#761=DIRECTION('',(0.,0.,1.));
#762=DIRECTION('',(1.,0.,0.));
#763=AXIS2_PLACEMENT_3D('',#760,#761,#762);
#764=PLANE('',#763);
#765=CARTESIAN_POINT('',(0.,-44.25,11.));
#766=DIRECTION('',(0.,0.,1.));
#767=DIRECTION('',(1.,0.,0.));
#768=AXIS2_PLACEMENT_3D('',#765,#766,#767);
#769=CIRCLE('',#768,3.175);
#770=CARTESIAN_POINT('',(3.175,-44.25,11.));
#771=VERTEX_POINT('',#770);
#772=EDGE_CURVE('E1453',#771,#771,#769,.T.);
#773=ORIENTED_EDGE('',*,*,#772,.F.);
#774=EDGE_LOOP('',(#773));
#775=FACE_BOUND('',#774,.T.);
#776=CARTESIAN_POINT('',(0.,-25.2,11.));
#777=DIRECTION('',(0.,0.,1.));
#778=DIRECTION('',(1.,0.,0.));
#779=AXIS2_PLACEMENT_3D('',#776,#777,#778);
#780=CIRCLE('',#779,3.175);
#781=CARTESIAN_POINT('',(3.175,-25.2,11.));
#782=VERTEX_POINT('',#781);
#783=EDGE_CURVE('E1457',#782,#782,#780,.T.);
#784=ORIENTED_EDGE('',*,*,#783,.F.);
#785=EDGE_LOOP('',(#784));
#786=FACE_BOUND('',#785,.T.);
#787=DIRECTION('',(1.,0.,0.));
#788=VECTOR('',#787,1.);
#789=CARTESIAN_POINT('',(-11.,-17.5,11.));
#790=LINE('',#789,#788);
#791=CARTESIAN_POINT('',(-10.4999999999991,-17.5,11.));
#792=VERTEX_POINT('',#791);
#793=CARTESIAN_POINT('',(10.4999999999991,-17.5,11.));
#794=VERTEX_POINT('',#793);
#795=EDGE_CURVE('E562',#792,#794,#790,.T.);
#796=ORIENTED_EDGE('',*,*,#795,.F.);
#797=DIRECTION('',(0.,1.,0.));
#798=VECTOR('',#797,1.);
#799=CARTESIAN_POINT('',(-10.4999999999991,-60.5,11.));
#800=LINE('',#799,#798);
#801=CARTESIAN_POINT('',(-10.4999999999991,-60.5,11.));
#802=VERTEX_POINT('',#801);
#803=EDGE_CURVE('E362',#792,#802,#800,.F.);
#804=ORIENTED_EDGE('',*,*,#803,.T.);
#805=DIRECTION('',(1.,0.,0.));
#806=VECTOR('',#805,1.);
#807=CARTESIAN_POINT('',(-11.,-60.5,11.));
#808=LINE('',#807,#806);
#809=CARTESIAN_POINT('',(10.4999999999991,-60.5,11.));
#810=VERTEX_POINT('',#809);
#811=EDGE_CURVE('E550',#802,#810,#808,.T.);
#812=ORIENTED_EDGE('',*,*,#811,.T.);
#813=DIRECTION('',(0.,1.,0.));
#814=VECTOR('',#813,1.);
#815=CARTESIAN_POINT('',(10.4999999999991,-60.5,11.));
#816=LINE('',#815,#814);
#817=EDGE_CURVE('E359',#810,#794,#816,.T.);
#818=ORIENTED_EDGE('',*,*,#817,.T.);
#819=EDGE_LOOP('',(#796,#804,#812,#818));
#820=FACE_BOUND('',#819,.T.);
#821=ADVANCED_FACE('F660',(#775,#786,#820),#764,.T.);
#822=CARTESIAN_POINT('',(-11.,-60.5,-11.));
#823=DIRECTION('',(-1.,0.,0.));
#824=DIRECTION('',(0.,0.,1.));
#825=AXIS2_PLACEMENT_3D('',#822,#823,#824);
#826=PLANE('',#825);
#827=DIRECTION('',(0.,0.,1.));
#828=VECTOR('',#827,1.);
#829=CARTESIAN_POINT('',(-11.,-60.5,-11.));
#830=LINE('',#829,#828);
#831=CARTESIAN_POINT('',(-11.,-60.5,-10.4999999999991));
#832=VERTEX_POINT('',#831);
#833=CARTESIAN_POINT('',(-11.,-60.5,10.4999999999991));
#834=VERTEX_POINT('',#833);
#835=EDGE_CURVE('E546',#832,#834,#830,.T.);
#836=ORIENTED_EDGE('',*,*,#835,.T.);
#837=DIRECTION('',(0.,1.,0.));
#838=VECTOR('',#837,1.);
#839=CARTESIAN_POINT('',(-11.,-60.5,10.4999999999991));
#840=LINE('',#839,#838);
#841=CARTESIAN_POINT('',(-11.,-17.5,10.4999999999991));
#842=VERTEX_POINT('',#841);
#843=EDGE_CURVE('E348',#834,#842,#840,.T.);
#844=ORIENTED_EDGE('',*,*,#843,.T.);
#845=DIRECTION('',(0.,0.,1.));
#846=VECTOR('',#845,1.);
#847=CARTESIAN_POINT('',(-11.,-17.5,-11.));
#848=LINE('',#847,#846);
#849=CARTESIAN_POINT('',(-11.,-17.5,-10.4999999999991));
#850=VERTEX_POINT('',#849);
#851=EDGE_CURVE('E559',#850,#842,#848,.T.);
#852=ORIENTED_EDGE('',*,*,#851,.F.);
#853=DIRECTION('',(0.,1.,0.));
#854=VECTOR('',#853,1.);
#855=CARTESIAN_POINT('',(-11.,-60.5,-10.4999999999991));
#856=LINE('',#855,#854);
#857=EDGE_CURVE('E346',#850,#832,#856,.F.);
#858=ORIENTED_EDGE('',*,*,#857,.T.);
#859=EDGE_LOOP('',(#836,#844,#852,#858));
#860=FACE_BOUND('',#859,.T.);
#861=ADVANCED_FACE('F653',(#860),#826,.T.);
#862=CARTESIAN_POINT('',(0.,-60.5,0.));
#863=DIRECTION('',(0.,1.,0.));
#864=DIRECTION('',(0.,0.,1.));
#865=AXIS2_PLACEMENT_3D('',#862,#863,#864);
#866=PLANE('',#865);
#867=ORIENTED_EDGE('',*,*,#811,.F.);
#868=CARTESIAN_POINT('',(-10.4999999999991,-60.5,10.4999999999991));
#869=DIRECTION('',(0.,1.,0.));
#870=DIRECTION('',(0.,0.,1.));
#871=AXIS2_PLACEMENT_3D('',#868,#869,#870);
#872=CIRCLE('',#871,0.500000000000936);
#873=EDGE_CURVE('E370',#802,#834,#872,.F.);
#874=ORIENTED_EDGE('',*,*,#873,.T.);
#875=ORIENTED_EDGE('',*,*,#835,.F.);
#876=CARTESIAN_POINT('',(-10.4999999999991,-60.5,-10.4999999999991));
#877=DIRECTION('',(0.,1.,0.));
#878=DIRECTION('',(0.,0.,1.));
#879=AXIS2_PLACEMENT_3D('',#876,#877,#878);
#880=CIRCLE('',#879,0.500000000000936);
#881=EDGE_CURVE('E366',#832,#692,#880,.F.);
#882=ORIENTED_EDGE('',*,*,#881,.T.);
#883=ORIENTED_EDGE('',*,*,#693,.F.);
#884=CARTESIAN_POINT('',(10.4999999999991,-60.5,-10.4999999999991));
#885=DIRECTION('',(0.,1.,0.));
#886=DIRECTION('',(0.,0.,1.));
#887=AXIS2_PLACEMENT_3D('',#884,#885,#886);
#888=CIRCLE('',#887,0.500000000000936);
#889=EDGE_CURVE('E364',#690,#748,#888,.F.);
#890=ORIENTED_EDGE('',*,*,#889,.T.);
#891=ORIENTED_EDGE('',*,*,#749,.F.);
#892=CARTESIAN_POINT('',(10.4999999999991,-60.5,10.4999999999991));
#893=DIRECTION('',(0.,1.,0.));
#894=DIRECTION('',(0.,0.,1.));
#895=AXIS2_PLACEMENT_3D('',#892,#893,#894);
#896=CIRCLE('',#895,0.500000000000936);
#897=EDGE_CURVE('E368',#740,#810,#896,.F.);
#898=ORIENTED_EDGE('',*,*,#897,.T.);
#899=EDGE_LOOP('',(#867,#874,#875,#882,#883,#890,#891,#898));
#900=FACE_BOUND('',#899,.T.);
#901=ADVANCED_FACE('F650',(#900),#866,.F.);
#902=CARTESIAN_POINT('',(0.,-17.5,0.));
#903=DIRECTION('',(0.,1.,0.));
#904=DIRECTION('',(0.,0.,1.));
#905=AXIS2_PLACEMENT_3D('',#902,#903,#904);
#906=PLANE('',#905);
#907=ORIENTED_EDGE('',*,*,#292,.T.);
#908=ORIENTED_EDGE('',*,*,#255,.T.);
#909=ORIENTED_EDGE('',*,*,#428,.T.);
#910=ORIENTED_EDGE('',*,*,#318,.T.);
#911=EDGE_LOOP('',(#907,#908,#909,#910));
#912=FACE_BOUND('',#911,.T.);
#913=ORIENTED_EDGE('',*,*,#851,.T.);
#914=CARTESIAN_POINT('',(-10.4999999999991,-17.5,10.4999999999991));
#915=DIRECTION('',(0.,1.,0.));
#916=DIRECTION('',(0.,0.,1.));
#917=AXIS2_PLACEMENT_3D('',#914,#915,#916);
#918=CIRCLE('',#917,0.500000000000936);
#919=EDGE_CURVE('E357',#842,#792,#918,.T.);
#920=ORIENTED_EDGE('',*,*,#919,.T.);
#921=ORIENTED_EDGE('',*,*,#795,.T.);
#922=CARTESIAN_POINT('',(10.4999999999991,-17.5,10.4999999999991));
#923=DIRECTION('',(0.,1.,0.));
#924=DIRECTION('',(0.,0.,1.));
#925=AXIS2_PLACEMENT_3D('',#922,#923,#924);
#926=CIRCLE('',#925,0.500000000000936);
#927=EDGE_CURVE('E355',#794,#730,#926,.T.);
#928=ORIENTED_EDGE('',*,*,#927,.T.);
#929=ORIENTED_EDGE('',*,*,#733,.T.);
#930=CARTESIAN_POINT('',(10.4999999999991,-17.5,-10.4999999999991));
#931=DIRECTION('',(0.,1.,0.));
#932=DIRECTION('',(0.,0.,1.));
#933=AXIS2_PLACEMENT_3D('',#930,#931,#932);
#934=CIRCLE('',#933,0.500000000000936);
#935=EDGE_CURVE('E351',#732,#708,#934,.T.);
#936=ORIENTED_EDGE('',*,*,#935,.T.);
#937=ORIENTED_EDGE('',*,*,#709,.T.);
#938=CARTESIAN_POINT('',(-10.4999999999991,-17.5,-10.4999999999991));
#939=DIRECTION('',(0.,1.,0.));
#940=DIRECTION('',(0.,0.,1.));
#941=AXIS2_PLACEMENT_3D('',#938,#939,#940);
#942=CIRCLE('',#941,0.500000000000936);
#943=EDGE_CURVE('E353',#700,#850,#942,.T.);
#944=ORIENTED_EDGE('',*,*,#943,.T.);
#945=EDGE_LOOP('',(#913,#920,#921,#928,#929,#936,#937,#944));
#946=FACE_BOUND('',#945,.T.);
#947=ADVANCED_FACE('F648',(#912,#946),#906,.T.);
#948=CARTESIAN_POINT('',(0.,12.5,0.));
#949=DIRECTION('',(0.,-1.,0.));
#950=DIRECTION('',(1.,0.,0.));
#951=AXIS2_PLACEMENT_3D('',#948,#949,#950);
#952=PLANE('',#951);
#953=ORIENTED_EDGE('',*,*,#363,.T.);
#954=ORIENTED_EDGE('',*,*,#40,.F.);
#955=DIRECTION('',(0.,0.,-1.));
#956=VECTOR('',#955,1.);
#957=CARTESIAN_POINT('',(-12.5,12.5,-10.));
#958=LINE('',#957,#956);
#959=CARTESIAN_POINT('',(-12.5,12.5,12.5));
#960=VERTEX_POINT('',#959);
#961=EDGE_CURVE('E524',#960,#31,#958,.T.);
#962=ORIENTED_EDGE('',*,*,#961,.F.);
#963=DIRECTION('',(-1.,0.,0.));
#964=VECTOR('',#963,1.);
#965=CARTESIAN_POINT('',(-10.,12.5,12.5));
#966=LINE('',#965,#964);
#967=EDGE_CURVE('E535',#362,#960,#966,.T.);
#968=ORIENTED_EDGE('',*,*,#967,.F.);
#969=EDGE_LOOP('',(#953,#954,#962,#968));
#970=FACE_BOUND('',#969,.T.);
#971=ADVANCED_FACE('F644',(#970),#952,.F.);
#972=CARTESIAN_POINT('',(0.,0.,12.5));
#973=DIRECTION('',(0.,0.,-1.));
#974=DIRECTION('',(-1.,0.,0.));
#975=AXIS2_PLACEMENT_3D('',#972,#973,#974);
#976=PLANE('',#975);
#977=ORIENTED_EDGE('',*,*,#967,.T.);
#978=DIRECTION('',(0.,1.,0.));
#979=VECTOR('',#978,1.);
#980=CARTESIAN_POINT('',(-12.5,12.5,12.5));
#981=LINE('',#980,#979);
#982=EDGE_CURVE('E521',#394,#960,#981,.T.);
#983=ORIENTED_EDGE('',*,*,#982,.F.);
#984=ORIENTED_EDGE('',*,*,#395,.T.);
#985=ORIENTED_EDGE('',*,*,#371,.T.);
#986=EDGE_LOOP('',(#977,#983,#984,#985));
#987=FACE_BOUND('',#986,.T.);
#988=ADVANCED_FACE('F640',(#987),#976,.F.);
#989=CARTESIAN_POINT('',(-12.5,0.,0.));
#990=DIRECTION('',(1.,0.,0.));
#991=DIRECTION('',(0.,0.,-1.));
#992=AXIS2_PLACEMENT_3D('',#989,#990,#991);
#993=PLANE('',#992);
#994=ORIENTED_EDGE('',*,*,#961,.T.);
#995=ORIENTED_EDGE('',*,*,#32,.F.);
#996=ORIENTED_EDGE('',*,*,#401,.T.);
#997=ORIENTED_EDGE('',*,*,#982,.T.);
#998=EDGE_LOOP('',(#994,#995,#996,#997));
#999=FACE_BOUND('',#998,.T.);
#1000=ADVANCED_FACE('F637',(#999),#993,.F.);
#1001=CARTESIAN_POINT('',(0.,-11.,0.));
#1002=DIRECTION('',(0.,1.,0.));
#1003=DIRECTION('',(0.,0.,1.));
#1004=AXIS2_PLACEMENT_3D('',#1001,#1002,#1003);
#1005=PLANE('',#1004);
#1006=ORIENTED_EDGE('',*,*,#566,.T.);
#1007=DIRECTION('',(1.,0.,0.));
#1008=VECTOR('',#1007,1.);
#1009=CARTESIAN_POINT('',(0.,-11.,10.4999999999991));
#1010=LINE('',#1009,#1008);
#1011=EDGE_CURVE('E389',#557,#610,#1010,.F.);
#1012=ORIENTED_EDGE('',*,*,#1011,.T.);
#1013=ORIENTED_EDGE('',*,*,#613,.T.);
#1014=DIRECTION('',(1.,0.,0.));
#1015=VECTOR('',#1014,1.);
#1016=CARTESIAN_POINT('',(0.,-11.,-10.4999999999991));
#1017=LINE('',#1016,#1015);
#1018=EDGE_CURVE('E386',#612,#565,#1017,.T.);
#1019=ORIENTED_EDGE('',*,*,#1018,.T.);
#1020=EDGE_LOOP('',(#1006,#1012,#1013,#1019));
#1021=FACE_BOUND('',#1020,.T.);
#1022=ADVANCED_FACE('F598',(#1021),#1005,.F.);
#1023=CARTESIAN_POINT('',(0.,0.,11.));
#1024=DIRECTION('',(0.,0.,-1.));
#1025=DIRECTION('',(-1.,0.,0.));
#1026=AXIS2_PLACEMENT_3D('',#1023,#1024,#1025);
#1027=PLANE('',#1026);
#1028=CARTESIAN_POINT('',(44.25,0.,11.));
#1029=DIRECTION('',(0.,0.,1.));
#1030=DIRECTION('',(1.,0.,0.));
#1031=AXIS2_PLACEMENT_3D('',#1028,#1029,#1030);
#1032=CIRCLE('',#1031,3.175);
#1033=CARTESIAN_POINT('',(47.425,0.,11.));
#1034=VERTEX_POINT('',#1033);
#1035=EDGE_CURVE('E1465',#1034,#1034,#1032,.T.);
#1036=ORIENTED_EDGE('',*,*,#1035,.F.);
#1037=EDGE_LOOP('',(#1036));
#1038=FACE_BOUND('',#1037,.T.);
#1039=CARTESIAN_POINT('',(25.2,0.,11.));
#1040=DIRECTION('',(0.,0.,1.));
#1041=DIRECTION('',(1.,0.,0.));
#1042=AXIS2_PLACEMENT_3D('',#1039,#1040,#1041);
#1043=CIRCLE('',#1042,3.175);
#1044=CARTESIAN_POINT('',(28.375,0.,11.));
#1045=VERTEX_POINT('',#1044);
#1046=EDGE_CURVE('E1468',#1045,#1045,#1043,.T.);
#1047=ORIENTED_EDGE('',*,*,#1046,.F.);
#1048=EDGE_LOOP('',(#1047));
#1049=FACE_BOUND('',#1048,.T.);
#1050=ORIENTED_EDGE('',*,*,#630,.T.);
#1051=DIRECTION('',(1.,0.,0.));
#1052=VECTOR('',#1051,1.);
#1053=CARTESIAN_POINT('',(0.,-10.4999999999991,11.));
#1054=LINE('',#1053,#1052);
#1055=EDGE_CURVE('E375',#621,#546,#1054,.T.);
#1056=ORIENTED_EDGE('',*,*,#1055,.T.);
#1057=ORIENTED_EDGE('',*,*,#549,.T.);
#1058=DIRECTION('',(-1.,0.,0.));
#1059=VECTOR('',#1058,1.);
#1060=CARTESIAN_POINT('',(0.,10.4999999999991,11.));
#1061=LINE('',#1060,#1059);
#1062=EDGE_CURVE('E372',#548,#629,#1061,.T.);
#1063=ORIENTED_EDGE('',*,*,#1062,.T.);
#1064=EDGE_LOOP('',(#1050,#1056,#1057,#1063));
#1065=FACE_BOUND('',#1064,.T.);
#1066=ADVANCED_FACE('F589',(#1038,#1049,#1065),#1027,.F.);
#1067=CARTESIAN_POINT('',(-11.,11.,-60.5));
#1068=DIRECTION('',(1.,0.,0.));
#1069=DIRECTION('',(0.,0.,-1.));
#1070=AXIS2_PLACEMENT_3D('',#1067,#1068,#1069);
#1071=PLANE('',#1070);
#1072=CARTESIAN_POINT('',(-11.,0.,-25.2));
#1073=DIRECTION('',(-1.,0.,0.));
#1074=DIRECTION('',(0.,0.,1.));
#1075=AXIS2_PLACEMENT_3D('',#1072,#1073,#1074);
#1076=CIRCLE('',#1075,3.175);
#1077=CARTESIAN_POINT('',(-11.,0.,-22.025));
#1078=VERTEX_POINT('',#1077);
#1079=EDGE_CURVE('E1442',#1078,#1078,#1076,.T.);
#1080=ORIENTED_EDGE('',*,*,#1079,.F.);
#1081=EDGE_LOOP('',(#1080));
#1082=FACE_BOUND('',#1081,.T.);
#1083=CARTESIAN_POINT('',(-11.,0.,-44.25));
#1084=DIRECTION('',(-1.,0.,0.));
#1085=DIRECTION('',(0.,0.,1.));
#1086=AXIS2_PLACEMENT_3D('',#1083,#1084,#1085);
#1087=CIRCLE('',#1086,3.175);
#1088=CARTESIAN_POINT('',(-11.,0.,-41.075));
#1089=VERTEX_POINT('',#1088);
#1090=EDGE_CURVE('E1443',#1089,#1089,#1087,.T.);
#1091=ORIENTED_EDGE('',*,*,#1090,.F.);
#1092=EDGE_LOOP('',(#1091));
#1093=FACE_BOUND('',#1092,.T.);
#1094=ORIENTED_EDGE('',*,*,#66,.T.);
#1095=DIRECTION('',(0.,0.,1.));
#1096=VECTOR('',#1095,1.);
#1097=CARTESIAN_POINT('',(-11.,10.4999999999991,-60.5));
#1098=LINE('',#1097,#1096);
#1099=CARTESIAN_POINT('',(-11.,10.4999999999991,-60.5));
#1100=VERTEX_POINT('',#1099);
#1101=EDGE_CURVE('E438',#65,#1100,#1098,.F.);
#1102=ORIENTED_EDGE('',*,*,#1101,.T.);
#1103=DIRECTION('',(0.,1.,0.));
#1104=VECTOR('',#1103,1.);
#1105=CARTESIAN_POINT('',(-11.,11.,-60.5));
#1106=LINE('',#1105,#1104);
#1107=CARTESIAN_POINT('',(-11.,-10.4999999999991,-60.5));
#1108=VERTEX_POINT('',#1107);
#1109=EDGE_CURVE('E478',#1108,#1100,#1106,.T.);
#1110=ORIENTED_EDGE('',*,*,#1109,.F.);
#1111=DIRECTION('',(0.,0.,1.));
#1112=VECTOR('',#1111,1.);
#1113=CARTESIAN_POINT('',(-11.,-10.4999999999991,-60.5));
#1114=LINE('',#1113,#1112);
#1115=EDGE_CURVE('E436',#1108,#63,#1114,.T.);
#1116=ORIENTED_EDGE('',*,*,#1115,.T.);
#1117=EDGE_LOOP('',(#1094,#1102,#1110,#1116));
#1118=FACE_BOUND('',#1117,.T.);
#1119=ADVANCED_FACE('F846',(#1082,#1093,#1118),#1071,.F.);
#1120=CARTESIAN_POINT('',(11.,11.,-60.5));
#1121=DIRECTION('',(0.,-1.,0.));
#1122=DIRECTION('',(0.,0.,-1.));
#1123=AXIS2_PLACEMENT_3D('',#1120,#1121,#1122);
#1124=PLANE('',#1123);
#1125=ORIENTED_EDGE('',*,*,#117,.T.);
#1126=DIRECTION('',(0.,0.,1.));
#1127=VECTOR('',#1126,1.);
#1128=CARTESIAN_POINT('',(10.4999999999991,11.,-60.5));
#1129=LINE('',#1128,#1127);
#1130=CARTESIAN_POINT('',(10.4999999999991,11.,-60.5));
#1131=VERTEX_POINT('',#1130);
#1132=EDGE_CURVE('E434',#108,#1131,#1129,.F.);
#1133=ORIENTED_EDGE('',*,*,#1132,.T.);
#1134=DIRECTION('',(1.,0.,0.));
#1135=VECTOR('',#1134,1.);
#1136=CARTESIAN_POINT('',(11.,11.,-60.5));
#1137=LINE('',#1136,#1135);
#1138=CARTESIAN_POINT('',(-10.4999999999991,11.,-60.5));
#1139=VERTEX_POINT('',#1138);
#1140=EDGE_CURVE('E471',#1139,#1131,#1137,.T.);
#1141=ORIENTED_EDGE('',*,*,#1140,.F.);
#1142=DIRECTION('',(0.,0.,1.));
#1143=VECTOR('',#1142,1.);
#1144=CARTESIAN_POINT('',(-10.4999999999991,11.,-60.5));
#1145=LINE('',#1144,#1143);
#1146=EDGE_CURVE('E431',#1139,#116,#1145,.T.);
#1147=ORIENTED_EDGE('',*,*,#1146,.T.);
#1148=EDGE_LOOP('',(#1125,#1133,#1141,#1147));
#1149=FACE_BOUND('',#1148,.T.);
#1150=ADVANCED_FACE('F457',(#1149),#1124,.F.);
#1151=CARTESIAN_POINT('',(11.,-11.,-60.5));
#1152=DIRECTION('',(-1.,0.,0.));
#1153=DIRECTION('',(0.,0.,1.));
#1154=AXIS2_PLACEMENT_3D('',#1151,#1152,#1153);
#1155=PLANE('',#1154);
#1156=CARTESIAN_POINT('',(11.,0.,-25.2));
#1157=DIRECTION('',(-1.,0.,0.));
#1158=DIRECTION('',(0.,0.,1.));
#1159=AXIS2_PLACEMENT_3D('',#1156,#1157,#1158);
#1160=CIRCLE('',#1159,3.175);
#1161=CARTESIAN_POINT('',(11.,0.,-22.025));
#1162=VERTEX_POINT('',#1161);
#1163=EDGE_CURVE('E1439',#1162,#1162,#1160,.F.);
#1164=ORIENTED_EDGE('',*,*,#1163,.F.);
#1165=EDGE_LOOP('',(#1164));
#1166=FACE_BOUND('',#1165,.T.);
#1167=CARTESIAN_POINT('',(11.,0.,-44.25));
#1168=DIRECTION('',(-1.,0.,0.));
#1169=DIRECTION('',(0.,0.,1.));
#1170=AXIS2_PLACEMENT_3D('',#1167,#1168,#1169);
#1171=CIRCLE('',#1170,3.175);
#1172=CARTESIAN_POINT('',(11.,0.,-41.075));
#1173=VERTEX_POINT('',#1172);
#1174=EDGE_CURVE('E1448',#1173,#1173,#1171,.F.);
#1175=ORIENTED_EDGE('',*,*,#1174,.F.);
#1176=EDGE_LOOP('',(#1175));
#1177=FACE_BOUND('',#1176,.T.);
#1178=ORIENTED_EDGE('',*,*,#100,.T.);
#1179=DIRECTION('',(0.,0.,1.));
#1180=VECTOR('',#1179,1.);
#1181=CARTESIAN_POINT('',(11.,-10.4999999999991,-60.5));
#1182=LINE('',#1181,#1180);
#1183=CARTESIAN_POINT('',(11.,-10.4999999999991,-60.5));
#1184=VERTEX_POINT('',#1183);
#1185=EDGE_CURVE('E416',#91,#1184,#1182,.F.);
#1186=ORIENTED_EDGE('',*,*,#1185,.T.);
#1187=DIRECTION('',(0.,-1.,0.));
#1188=VECTOR('',#1187,1.);
#1189=CARTESIAN_POINT('',(11.,-11.,-60.5));
#1190=LINE('',#1189,#1188);
#1191=CARTESIAN_POINT('',(11.,10.4999999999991,-60.5));
#1192=VERTEX_POINT('',#1191);
#1193=EDGE_CURVE('E469',#1192,#1184,#1190,.T.);
#1194=ORIENTED_EDGE('',*,*,#1193,.F.);
#1195=DIRECTION('',(0.,0.,1.));
#1196=VECTOR('',#1195,1.);
#1197=CARTESIAN_POINT('',(11.,10.4999999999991,-60.5));
#1198=LINE('',#1197,#1196);
#1199=EDGE_CURVE('E413',#1192,#99,#1198,.T.);
#1200=ORIENTED_EDGE('',*,*,#1199,.T.);
#1201=EDGE_LOOP('',(#1178,#1186,#1194,#1200));
#1202=FACE_BOUND('',#1201,.T.);
#1203=ADVANCED_FACE('F473',(#1166,#1177,#1202),#1155,.F.);
#1204=CARTESIAN_POINT('',(-11.,-11.,-60.5));
#1205=DIRECTION('',(0.,1.,0.));
#1206=DIRECTION('',(0.,0.,1.));
#1207=AXIS2_PLACEMENT_3D('',#1204,#1205,#1206);
#1208=PLANE('',#1207);
#1209=DIRECTION('',(-1.,0.,0.));
#1210=VECTOR('',#1209,1.);
#1211=CARTESIAN_POINT('',(-11.,-11.,-60.5));
#1212=LINE('',#1211,#1210);
#1213=CARTESIAN_POINT('',(10.4999999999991,-11.,-60.5));
#1214=VERTEX_POINT('',#1213);
#1215=CARTESIAN_POINT('',(-10.4999999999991,-11.,-60.5));
#1216=VERTEX_POINT('',#1215);
#1217=EDGE_CURVE('E289',#1214,#1216,#1212,.T.);
#1218=ORIENTED_EDGE('',*,*,#1217,.F.);
#1219=DIRECTION('',(0.,0.,1.));
#1220=VECTOR('',#1219,1.);
#1221=CARTESIAN_POINT('',(10.4999999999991,-11.,-60.5));
#1222=LINE('',#1221,#1220);
#1223=EDGE_CURVE('E410',#1214,#82,#1222,.T.);
#1224=ORIENTED_EDGE('',*,*,#1223,.T.);
#1225=ORIENTED_EDGE('',*,*,#83,.T.);
#1226=DIRECTION('',(0.,0.,1.));
#1227=VECTOR('',#1226,1.);
#1228=CARTESIAN_POINT('',(-10.4999999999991,-11.,-60.5));
#1229=LINE('',#1228,#1227);
#1230=EDGE_CURVE('E408',#74,#1216,#1229,.F.);
#1231=ORIENTED_EDGE('',*,*,#1230,.T.);
#1232=EDGE_LOOP('',(#1218,#1224,#1225,#1231));
#1233=FACE_BOUND('',#1232,.T.);
#1234=ADVANCED_FACE('F875',(#1233),#1208,.F.);
#1235=CARTESIAN_POINT('',(0.,0.,-60.5));
#1236=DIRECTION('',(0.,0.,1.));
#1237=DIRECTION('',(1.,0.,0.));
#1238=AXIS2_PLACEMENT_3D('',#1235,#1236,#1237);
#1239=PLANE('',#1238);
#1240=ORIENTED_EDGE('',*,*,#1193,.T.);
#1241=CARTESIAN_POINT('',(10.4999999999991,-10.4999999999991,-60.5));
#1242=DIRECTION('',(0.,0.,1.));
#1243=DIRECTION('',(1.,0.,0.));
#1244=AXIS2_PLACEMENT_3D('',#1241,#1242,#1243);
#1245=CIRCLE('',#1244,0.500000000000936);
#1246=EDGE_CURVE('E424',#1184,#1214,#1245,.F.);
#1247=ORIENTED_EDGE('',*,*,#1246,.T.);
#1248=ORIENTED_EDGE('',*,*,#1217,.T.);
#1249=CARTESIAN_POINT('',(-10.4999999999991,-10.4999999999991,-60.5));
#1250=DIRECTION('',(0.,0.,1.));
#1251=DIRECTION('',(1.,0.,0.));
#1252=AXIS2_PLACEMENT_3D('',#1249,#1250,#1251);
#1253=CIRCLE('',#1252,0.500000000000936);
#1254=EDGE_CURVE('E418',#1216,#1108,#1253,.F.);
#1255=ORIENTED_EDGE('',*,*,#1254,.T.);
#1256=ORIENTED_EDGE('',*,*,#1109,.T.);
#1257=CARTESIAN_POINT('',(-10.4999999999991,10.4999999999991,-60.5));
#1258=DIRECTION('',(0.,0.,1.));
#1259=DIRECTION('',(1.,0.,0.));
#1260=AXIS2_PLACEMENT_3D('',#1257,#1258,#1259);
#1261=CIRCLE('',#1260,0.500000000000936);
#1262=EDGE_CURVE('E420',#1100,#1139,#1261,.F.);
#1263=ORIENTED_EDGE('',*,*,#1262,.T.);
#1264=ORIENTED_EDGE('',*,*,#1140,.T.);
#1265=CARTESIAN_POINT('',(10.4999999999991,10.4999999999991,-60.5));
#1266=DIRECTION('',(0.,0.,1.));
#1267=DIRECTION('',(1.,0.,0.));
#1268=AXIS2_PLACEMENT_3D('',#1265,#1266,#1267);
#1269=CIRCLE('',#1268,0.500000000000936);
#1270=EDGE_CURVE('E422',#1131,#1192,#1269,.F.);
#1271=ORIENTED_EDGE('',*,*,#1270,.T.);
#1272=EDGE_LOOP('',(#1240,#1247,#1248,#1255,#1256,#1263,#1264,#1271));
#1273=FACE_BOUND('',#1272,.T.);
#1274=ADVANCED_FACE('F468',(#1273),#1239,.F.);
#1275=CARTESIAN_POINT('',(-10.4999999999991,-60.5,10.4999999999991));
#1276=DIRECTION('',(0.,1.,0.));
#1277=DIRECTION('',(0.,0.,1.));
#1278=AXIS2_PLACEMENT_3D('',#1275,#1276,#1277);
#1279=CYLINDRICAL_SURFACE('',#1278,0.500000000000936);
#1280=ORIENTED_EDGE('',*,*,#873,.F.);
#1281=ORIENTED_EDGE('',*,*,#803,.F.);
#1282=ORIENTED_EDGE('',*,*,#919,.F.);
#1283=ORIENTED_EDGE('',*,*,#843,.F.);
#1284=EDGE_LOOP('',(#1280,#1281,#1282,#1283));
#1285=FACE_BOUND('',#1284,.T.);
#1286=ADVANCED_FACE('F676',(#1285),#1279,.T.);
#1287=CARTESIAN_POINT('',(0.,-10.4999999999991,10.4999999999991));
#1288=DIRECTION('',(1.,0.,0.));
#1289=DIRECTION('',(0.,0.,-1.));
#1290=AXIS2_PLACEMENT_3D('',#1287,#1288,#1289);
#1291=CYLINDRICAL_SURFACE('',#1290,0.500000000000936);
#1292=ORIENTED_EDGE('',*,*,#622,.F.);
#1293=ORIENTED_EDGE('',*,*,#1011,.F.);
#1294=ORIENTED_EDGE('',*,*,#558,.F.);
#1295=ORIENTED_EDGE('',*,*,#1055,.F.);
#1296=EDGE_LOOP('',(#1292,#1293,#1294,#1295));
#1297=FACE_BOUND('',#1296,.T.);
#1298=ADVANCED_FACE('F594',(#1297),#1291,.T.);
#1299=CARTESIAN_POINT('',(60.5,10.4999999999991,-10.4999999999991));
#1300=DIRECTION('',(-1.,0.,0.));
#1301=DIRECTION('',(0.,0.,1.));
#1302=AXIS2_PLACEMENT_3D('',#1299,#1300,#1301);
#1303=CYLINDRICAL_SURFACE('',#1302,0.500000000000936);
#1304=ORIENTED_EDGE('',*,*,#581,.F.);
#1305=ORIENTED_EDGE('',*,*,#477,.F.);
#1306=ORIENTED_EDGE('',*,*,#645,.F.);
#1307=ORIENTED_EDGE('',*,*,#517,.F.);
#1308=EDGE_LOOP('',(#1304,#1305,#1306,#1307));
#1309=FACE_BOUND('',#1308,.T.);
#1310=ADVANCED_FACE('F612',(#1309),#1303,.T.);
#1311=CARTESIAN_POINT('',(10.4999999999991,-10.4999999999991,-60.5));
#1312=DIRECTION('',(0.,0.,1.));
#1313=DIRECTION('',(1.,0.,0.));
#1314=AXIS2_PLACEMENT_3D('',#1311,#1312,#1313);
#1315=CYLINDRICAL_SURFACE('',#1314,0.500000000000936);
#1316=ORIENTED_EDGE('',*,*,#1246,.F.);
#1317=ORIENTED_EDGE('',*,*,#1185,.F.);
#1318=ORIENTED_EDGE('',*,*,#92,.F.);
#1319=ORIENTED_EDGE('',*,*,#1223,.F.);
#1320=EDGE_LOOP('',(#1316,#1317,#1318,#1319));
#1321=FACE_BOUND('',#1320,.T.);
#1322=ADVANCED_FACE('F718',(#1321),#1315,.T.);
#1323=CARTESIAN_POINT('',(10.4999999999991,-60.5,10.4999999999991));
#1324=DIRECTION('',(0.,1.,0.));
#1325=DIRECTION('',(0.,0.,1.));
#1326=AXIS2_PLACEMENT_3D('',#1323,#1324,#1325);
#1327=CYLINDRICAL_SURFACE('',#1326,0.500000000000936);
#1328=ORIENTED_EDGE('',*,*,#897,.F.);
#1329=ORIENTED_EDGE('',*,*,#741,.F.);
#1330=ORIENTED_EDGE('',*,*,#927,.F.);
#1331=ORIENTED_EDGE('',*,*,#817,.F.);
#1332=EDGE_LOOP('',(#1328,#1329,#1330,#1331));
#1333=FACE_BOUND('',#1332,.T.);
#1334=ADVANCED_FACE('F685',(#1333),#1327,.T.);
#1335=CARTESIAN_POINT('',(10.4999999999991,10.4999999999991,-60.5));
#1336=DIRECTION('',(0.,0.,1.));
#1337=DIRECTION('',(1.,0.,0.));
#1338=AXIS2_PLACEMENT_3D('',#1335,#1336,#1337);
#1339=CYLINDRICAL_SURFACE('',#1338,0.500000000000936);
#1340=ORIENTED_EDGE('',*,*,#1270,.F.);
#1341=ORIENTED_EDGE('',*,*,#1132,.F.);
#1342=ORIENTED_EDGE('',*,*,#109,.F.);
#1343=ORIENTED_EDGE('',*,*,#1199,.F.);
#1344=EDGE_LOOP('',(#1340,#1341,#1342,#1343));
#1345=FACE_BOUND('',#1344,.T.);
#1346=ADVANCED_FACE('F464',(#1345),#1339,.T.);
#1347=CARTESIAN_POINT('',(0.,10.4999999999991,10.4999999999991));
#1348=DIRECTION('',(-1.,0.,0.));
#1349=DIRECTION('',(0.,0.,1.));
#1350=AXIS2_PLACEMENT_3D('',#1347,#1348,#1349);
#1351=CYLINDRICAL_SURFACE('',#1350,0.500000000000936);
#1352=ORIENTED_EDGE('',*,*,#589,.F.);
#1353=ORIENTED_EDGE('',*,*,#531,.F.);
#1354=ORIENTED_EDGE('',*,*,#637,.F.);
#1355=ORIENTED_EDGE('',*,*,#1062,.F.);
#1356=EDGE_LOOP('',(#1352,#1353,#1354,#1355));
#1357=FACE_BOUND('',#1356,.T.);
#1358=ADVANCED_FACE('F583',(#1357),#1351,.T.);
#1359=CARTESIAN_POINT('',(-10.4999999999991,10.4999999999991,-60.5));
#1360=DIRECTION('',(0.,0.,1.));
#1361=DIRECTION('',(1.,0.,0.));
#1362=AXIS2_PLACEMENT_3D('',#1359,#1360,#1361);
#1363=CYLINDRICAL_SURFACE('',#1362,0.500000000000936);
#1364=ORIENTED_EDGE('',*,*,#1262,.F.);
#1365=ORIENTED_EDGE('',*,*,#1101,.F.);
#1366=ORIENTED_EDGE('',*,*,#124,.F.);
#1367=ORIENTED_EDGE('',*,*,#1146,.F.);
#1368=EDGE_LOOP('',(#1364,#1365,#1366,#1367));
#1369=FACE_BOUND('',#1368,.T.);
#1370=ADVANCED_FACE('F706',(#1369),#1363,.T.);
#1371=CARTESIAN_POINT('',(0.,-10.4999999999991,-10.4999999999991));
#1372=DIRECTION('',(1.,0.,0.));
#1373=DIRECTION('',(0.,0.,-1.));
#1374=AXIS2_PLACEMENT_3D('',#1371,#1372,#1373);
#1375=CYLINDRICAL_SURFACE('',#1374,0.500000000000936);
#1376=ORIENTED_EDGE('',*,*,#653,.F.);
#1377=ORIENTED_EDGE('',*,*,#491,.F.);
#1378=ORIENTED_EDGE('',*,*,#573,.F.);
#1379=ORIENTED_EDGE('',*,*,#1018,.F.);
#1380=EDGE_LOOP('',(#1376,#1377,#1378,#1379));
#1381=FACE_BOUND('',#1380,.T.);
#1382=ADVANCED_FACE('F603',(#1381),#1375,.T.);
#1383=CARTESIAN_POINT('',(-10.4999999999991,-60.5,-10.4999999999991));
#1384=DIRECTION('',(0.,1.,0.));
#1385=DIRECTION('',(0.,0.,1.));
#1386=AXIS2_PLACEMENT_3D('',#1383,#1384,#1385);
#1387=CYLINDRICAL_SURFACE('',#1386,0.500000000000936);
#1388=ORIENTED_EDGE('',*,*,#881,.F.);
#1389=ORIENTED_EDGE('',*,*,#857,.F.);
#1390=ORIENTED_EDGE('',*,*,#943,.F.);
#1391=ORIENTED_EDGE('',*,*,#701,.F.);
#1392=EDGE_LOOP('',(#1388,#1389,#1390,#1391));
#1393=FACE_BOUND('',#1392,.T.);
#1394=ADVANCED_FACE('F698',(#1393),#1387,.T.);
#1395=CARTESIAN_POINT('',(-10.4999999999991,-10.4999999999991,-60.5));
#1396=DIRECTION('',(0.,0.,1.));
#1397=DIRECTION('',(1.,0.,0.));
#1398=AXIS2_PLACEMENT_3D('',#1395,#1396,#1397);
#1399=CYLINDRICAL_SURFACE('',#1398,0.500000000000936);
#1400=ORIENTED_EDGE('',*,*,#1254,.F.);
#1401=ORIENTED_EDGE('',*,*,#1230,.F.);
#1402=ORIENTED_EDGE('',*,*,#75,.F.);
#1403=ORIENTED_EDGE('',*,*,#1115,.F.);
#1404=EDGE_LOOP('',(#1400,#1401,#1402,#1403));
#1405=FACE_BOUND('',#1404,.T.);
#1406=ADVANCED_FACE('F700',(#1405),#1399,.T.);
#1407=CARTESIAN_POINT('',(10.4999999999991,-60.5,-10.4999999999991));
#1408=DIRECTION('',(0.,1.,0.));
#1409=DIRECTION('',(0.,0.,1.));
#1410=AXIS2_PLACEMENT_3D('',#1407,#1408,#1409);
#1411=CYLINDRICAL_SURFACE('',#1410,0.500000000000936);
#1412=ORIENTED_EDGE('',*,*,#889,.F.);
#1413=ORIENTED_EDGE('',*,*,#715,.F.);
#1414=ORIENTED_EDGE('',*,*,#935,.F.);
#1415=ORIENTED_EDGE('',*,*,#755,.F.);
#1416=EDGE_LOOP('',(#1412,#1413,#1414,#1415));
#1417=FACE_BOUND('',#1416,.T.);
#1418=ADVANCED_FACE('F48',(#1417),#1411,.T.);
#1419=CARTESIAN_POINT('',(25.2,0.,-19.9802561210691));
#1420=DIRECTION('',(0.,0.,1.));
#1421=DIRECTION('',(1.,0.,0.));
#1422=AXIS2_PLACEMENT_3D('',#1419,#1420,#1421);
#1423=CYLINDRICAL_SURFACE('',#1422,3.175);
#1424=ORIENTED_EDGE('',*,*,#457,.T.);
#1425=EDGE_LOOP('',(#1424));
#1426=FACE_BOUND('',#1425,.T.);
#1427=ORIENTED_EDGE('',*,*,#1046,.T.);
#1428=EDGE_LOOP('',(#1427));
#1429=FACE_BOUND('',#1428,.T.);
#1430=ADVANCED_FACE('F966',(#1426,#1429),#1423,.F.);
#1431=CARTESIAN_POINT('',(44.25,0.,-19.9802561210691));
#1432=DIRECTION('',(0.,0.,1.));
#1433=DIRECTION('',(1.,0.,0.));
#1434=AXIS2_PLACEMENT_3D('',#1431,#1432,#1433);
#1435=CYLINDRICAL_SURFACE('',#1434,3.175);
#1436=ORIENTED_EDGE('',*,*,#446,.T.);
#1437=EDGE_LOOP('',(#1436));
#1438=FACE_BOUND('',#1437,.T.);
#1439=ORIENTED_EDGE('',*,*,#1035,.T.);
#1440=EDGE_LOOP('',(#1439));
#1441=FACE_BOUND('',#1440,.T.);
#1442=ADVANCED_FACE('F974',(#1438,#1441),#1435,.F.);
#1443=CARTESIAN_POINT('',(0.,-25.2,-19.9802561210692));
#1444=DIRECTION('',(0.,0.,1.));
#1445=DIRECTION('',(1.,0.,0.));
#1446=AXIS2_PLACEMENT_3D('',#1443,#1444,#1445);
#1447=CYLINDRICAL_SURFACE('',#1446,3.175);
#1448=ORIENTED_EDGE('',*,*,#783,.T.);
#1449=EDGE_LOOP('',(#1448));
#1450=FACE_BOUND('',#1449,.T.);
#1451=ORIENTED_EDGE('',*,*,#681,.F.);
#1452=EDGE_LOOP('',(#1451));
#1453=FACE_BOUND('',#1452,.T.);
#1454=ADVANCED_FACE('F984',(#1450,#1453),#1447,.F.);
#1455=CARTESIAN_POINT('',(0.,-44.25,-19.9802561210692));
#1456=DIRECTION('',(0.,0.,1.));
#1457=DIRECTION('',(1.,0.,0.));
#1458=AXIS2_PLACEMENT_3D('',#1455,#1456,#1457);
#1459=CYLINDRICAL_SURFACE('',#1458,3.175);
#1460=ORIENTED_EDGE('',*,*,#772,.T.);
#1461=EDGE_LOOP('',(#1460));
#1462=FACE_BOUND('',#1461,.T.);
#1463=ORIENTED_EDGE('',*,*,#670,.F.);
#1464=EDGE_LOOP('',(#1463));
#1465=FACE_BOUND('',#1464,.T.);
#1466=ADVANCED_FACE('F993',(#1462,#1465),#1459,.F.);
#1467=CARTESIAN_POINT('',(19.9802561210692,0.,-44.25));
#1468=DIRECTION('',(-1.,0.,0.));
#1469=DIRECTION('',(0.,0.,1.));
#1470=AXIS2_PLACEMENT_3D('',#1467,#1468,#1469);
#1471=CYLINDRICAL_SURFACE('',#1470,3.175);
#1472=ORIENTED_EDGE('',*,*,#1174,.T.);
#1473=EDGE_LOOP('',(#1472));
#1474=FACE_BOUND('',#1473,.T.);
#1475=ORIENTED_EDGE('',*,*,#1090,.T.);
#1476=EDGE_LOOP('',(#1475));
#1477=FACE_BOUND('',#1476,.T.);
#1478=ADVANCED_FACE('F1002',(#1474,#1477),#1471,.F.);
#1479=CARTESIAN_POINT('',(19.9802561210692,0.,-25.2));
#1480=DIRECTION('',(-1.,0.,0.));
#1481=DIRECTION('',(0.,0.,1.));
#1482=AXIS2_PLACEMENT_3D('',#1479,#1480,#1481);
#1483=CYLINDRICAL_SURFACE('',#1482,3.175);
#1484=ORIENTED_EDGE('',*,*,#1163,.T.);
#1485=EDGE_LOOP('',(#1484));
#1486=FACE_BOUND('',#1485,.T.);
#1487=ORIENTED_EDGE('',*,*,#1079,.T.);
#1488=EDGE_LOOP('',(#1487));
#1489=FACE_BOUND('',#1488,.T.);
#1490=ADVANCED_FACE('F1012',(#1486,#1489),#1483,.F.);
#1491=CLOSED_SHELL('',(#128,#168,#199,#230,#265,#296,#322,#344,#381,#416,#433,#495,#535,#593,
#657,#719,#759,#821,#861,#901,#947,#971,#988,#1000,#1022,#1066,#1119,#1150,#1203,#1234,#1274,
#1286,#1298,#1310,#1322,#1334,#1346,#1358,#1370,#1382,#1394,#1406,#1418,#1430,#1442,#1454,#1466,
#1478,#1490));
#1492=MANIFOLD_SOLID_BREP('B2',#1491);
#1493=ADVANCED_BREP_SHAPE_REPRESENTATION('',(#18,#1492),#14);
#1494=SHAPE_DEFINITION_REPRESENTATION(#9,#1493);
ENDSEC;
END-ISO-10303-21;
